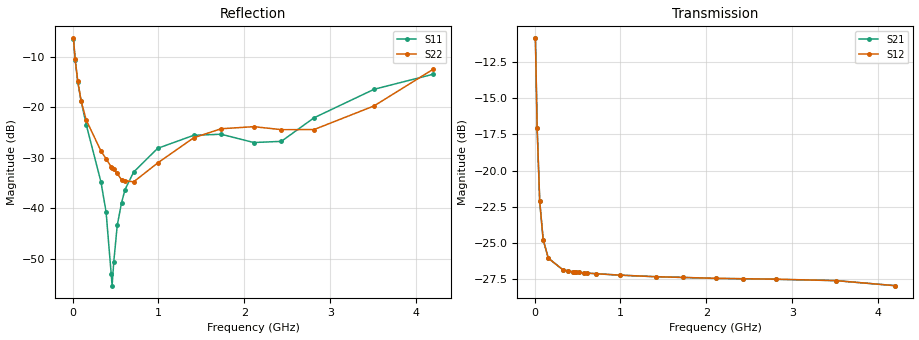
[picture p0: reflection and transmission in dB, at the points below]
! Integrated Device Technology
! Corporate Headquarters
! 6024 Silver Creek Valley Road
! San Jose, CA 95138  USA
! Phone:  1-408-284-8200
! Toll Free:  1-800-223-1366
! Webpage:  http://www.idt.com/
! Timing and RF Division
! 515 Groton Road, Suite 102
! Westford, MA 01886-6024
! Device:  F1950
! Description: 7-bit 0.25 dB Digital Step Attenuator
! Frequency:  150.0 -  4000.00 MHz
! Package:  4x4 mm Thin QFN Plastic Package: 24 pin
! Ports:  2 RF, 12 DC
!  Pin  1  = D0
!  Pin  2  = VDD
!  Pin  3  = Vmode
!  Pin  4  = GND
!  Pin  5  = RF1  =  Port 1
!  Pin  6  = GND
!  Pin  7  = GND
!  Pin  8  = GND
!  Pin  9  = GND
!  Pin 10  = GND
!  Pin 11  = GND
!  Pin 12  = GND
!  Pin 13  = GND
!  Pin 14  = RF2  =  Port 2
!  Pin 15  = GND
!  Pin 16  = LE
!  Pin 17  = CLK
!  Pin 18  = DATE
!  Pin 19  = D6
!  Pin 20  = D5
!  Pin 21  = D4
!  Pin 22  = D3
!  Pin 23  = D2
!  Pin 24  = D1
! State:  105
! Atten State:  26.25 dB
! Voltage:  +5.00 Volts
! Current:  Not Measured mA
! Data:  The device was measured on a the F195X evaluation board which has
!  individual transmission lines to the RF pins.  Data was collected
!  using a calibrated network analyzer.  The evaluation board was
!  de-embedded using a TRL calibration technique.
!  The reference plane is the edge of the package pin.
! Misc:  Board 2019
!  Action Tracker AT0250
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# GHz S dB R 50
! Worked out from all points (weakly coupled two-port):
!   420 points, 10 MHz to 4.2 GHz, reference 50 ohm
!   highest |S21| = -10.86 dB at 10 MHz (marker M1); lowest = -27.9 dB at 4.2 GHz (marker M2)
!   lowest |S11| = -55.3 dB at 460 MHz (marker M3), VSWR 1.00, Z = 49.9 - j0.0893 ohm
!   |S11| at or under -10 dB: 27.11 MHz to end of sweep
!   |S22| runs from -35.1 to -6.4 dB; largest |S21 - S12| = 8.9e-05
!   S11 on the Smith chart (normalised r, x): 10 MHz: 2.03, -1.16; 30 MHz: 1.28, -0.64; 60 MHz: 1.11, -0.37; 390 MHz: 1.01, -0.02; 4.2 GHz: 0.68, +0.17
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0.01  -6.41 -27.4  -10.86 -35.7  -10.86 -35.7  -6.37 -28.3
0.03  -10.56 -50.7  -17.03 -55.2  -17.03 -55.2  -10.50 -52.1
0.06  -14.98 -63.6  -22.13 -50.2  -22.13 -50.2  -14.77 -65.1
0.1  -18.85 -70.4  -24.76 -38.4  -24.76 -38.4  -18.84 -70.7
0.16  -23.52 -72.3  -26.05 -27.6  -26.05 -27.6  -22.57 -75.8
0.33  -34.77 -71.6  -26.85 -17.2  -26.85 -17.2  -28.66 -84.4
0.39  -40.73 -72.6  -26.93 -15.9  -26.93 -15.9  -30.21 -87.0
0.45  -53.08 -114.2  -26.99 -15.1  -26.98 -15.1  -31.83 -93.7
0.46  -55.33 -148.5  -26.99 -15.0  -26.99 -15.0  -32.02 -95.4
0.48  -50.55 155.7  -27.01 -14.9  -27.01 -14.9  -32.32 -98.4
0.52  -43.36 141.4  -27.03 -14.6  -27.03 -14.6  -33.11 -101.8
0.57  -38.92 135.8  -27.06 -14.5  -27.06 -14.5  -34.37 -111.7
0.61  -36.33 137.2  -27.08 -14.4  -27.08 -14.4  -34.52 -120.1
0.71  -32.85 138.3  -27.12 -14.5  -27.12 -14.5  -34.79 -139.6
0.99  -28.14 147.6  -27.22 -15.8  -27.22 -15.8  -31.04 179.9
1.41  -25.56 163.1  -27.33 -18.7  -27.33 -18.7  -26.05 160.4
1.73  -25.35 168.5  -27.38 -21.2  -27.38 -21.1  -24.26 152.0
2.11  -26.99 158.2  -27.45 -24.8  -27.44 -24.8  -23.85 142.2
2.43  -26.76 126.8  -27.47 -27.4  -27.47 -27.4  -24.44 131.4
2.81  -22.10 105.7  -27.51 -31.2  -27.50 -31.2  -24.43 116.1
3.51  -16.45 117.6  -27.60 -37.6  -27.60 -37.7  -19.74 113.3
4.2  -13.46 145.8  -27.95 -41.7  -27.95 -41.8  -12.46 127.2
